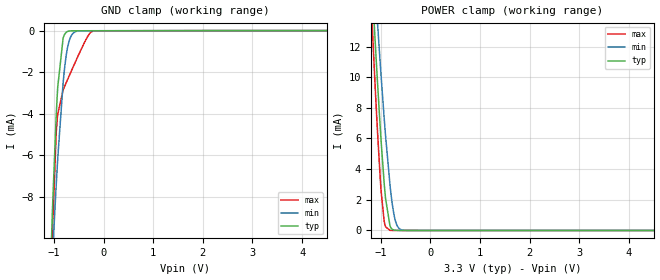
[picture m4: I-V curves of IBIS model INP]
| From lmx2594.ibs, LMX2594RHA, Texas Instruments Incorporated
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|   Model INP
[Model]   INP
Model_type   Input
Vinl = .4
Vinh = 1.4
|   typ   min   max
|   (nom PVT)   (slow PVT)   (fast PVT)
C_comp   0.097p   0.055p   0.172p
[Voltage Range]   3.3   3   3.6
[Temperature Range]   27   125   -40
[Power Clamp Reference]   3.3   3   3.6
[GND Clamp Reference]   0   0   0
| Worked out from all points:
|   GND clamp passes 1 mA (typ) near -0.84 V on its own axis
|   POWER clamp passes 1 mA (typ) near -0.85 V on its own axis
[GND Clamp]
|   Voltage   I(typ)   I(min)   I(max)
-3.3V     -246.7mA   -151.3mA   -472.5mA
-1.063V   -10.99mA   -12.47mA   -13.38mA
-1.043V   -9.526mA   -11.49mA   -11.15mA
-1.033V   -8.823mA   -11.01mA   -10.14mA
-1.023V   -8.14mA    -10.54mA   -9.21mA
-953.7mV  -4.036mA   -7.394mA   -4.875mA
-924mV    -2.719mA   -6.164mA   -4.026mA
-815.1mV  -359.4uA   -2.508mA   -2.855mA
-726mV    -41.2uA    -819.4uA   -2.358mA
-597.3mV  -10.68uA   -94.98uA   -1.663mA
-211.2mV  -9.103uA   -7.806uA   -22.77uA
6.6V      0A         0A         0A
[POWER Clamp]
|   Voltage   I(typ)   I(min)   I(max)
-3.3V     164.1mA    142.7mA    184.6mA
-1.27V    21.95mA    24.01mA    20.35mA
-1.162V   15.17mA    18.29mA    12.57mA
-1.112V   12.23mA    15.77mA    9.255mA
-1.073V   9.96mA     13.8mA     6.765mA
-993.3mV  5.782mA    10.03mA    2.547mA
-924mV    2.765mA    6.978mA    472uA
-815.1mV  299.5uA    2.966mA    9.519uA
-755.7mV  53.96uA    1.431mA    2.479uA
-696.3mV  9.978uA    523.6uA    1.72uA
-537.9mV  1.219uA    16.89uA    1.015uA
6.6V      0A         0A         0A
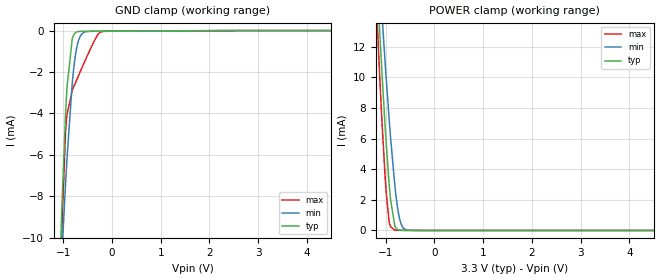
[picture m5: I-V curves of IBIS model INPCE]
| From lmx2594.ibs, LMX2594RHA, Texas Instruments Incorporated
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|   Model INPCE
[Model]   INPCE
Model_type   Input
Vinl = .4
Vinh = 1.4
|   typ   min   max
|   (nom PVT)   (slow PVT)   (fast PVT)
C_comp   0.097p   0.055p   0.172p
[Voltage Range]   3.3   3   3.6
[Temperature Range]   27   125   -40
[Power Clamp Reference]   3.3   3   3.6
[GND Clamp Reference]   0   0   0
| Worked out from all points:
|   GND clamp passes 1 mA (typ) near -0.84 V on its own axis
|   POWER clamp passes 1 mA (typ) near -0.85 V on its own axis
[GND Clamp]
|   Voltage   I(typ)   I(min)   I(max)
-3.3V     -246.7mA   -151.3mA   -472.6mA
-1.063V   -11.02mA   -12.49mA   -13.41mA
-1.043V   -9.555mA   -11.52mA   -11.18mA
-1.033V   -8.852mA   -11.04mA   -10.17mA
-1.023V   -8.169mA   -10.56mA   -9.241mA
-953.7mV  -4.065mA   -7.42mA    -4.906mA
-924mV    -2.747mA   -6.19mA    -4.056mA
-815.1mV  -386.5uA   -2.533mA   -2.884mA
-726mV    -67.58uA   -843.8uA   -2.387mA
-597.3mV  -35.97uA   -118.2uA   -1.691mA
-201.3mV  -31.01uA   -27.72uA   -42.5uA
6.6V      0A         0A         0A
[POWER Clamp]
|   Voltage   I(typ)   I(min)   I(max)
-3.3V     164.1mA    142.7mA    184.6mA
-1.27V    21.97mA    24.03mA    20.37mA
-1.162V   15.19mA    18.31mA    12.59mA
-1.112V   12.24mA    15.79mA    9.272mA
-1.073V   9.975mA    13.82mA    6.781mA
-993.3mV  5.796mA    10.04mA    2.561mA
-924mV    2.777mA    6.991mA    484.6uA
-815.1mV  309.7uA    2.977mA    19.73uA
-755.7mV  63.05uA    1.441mA    11.38uA
-696.3mV  17.92uA    532.6uA    9.321uA
-537.9mV  6.163uA    23.15uA    5.233uA
6.6V      0A         0A         0A
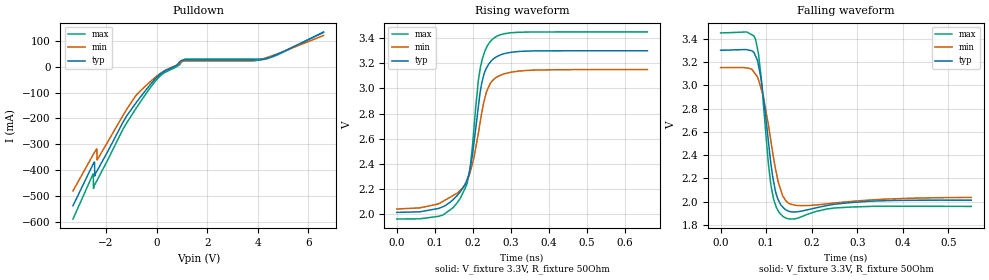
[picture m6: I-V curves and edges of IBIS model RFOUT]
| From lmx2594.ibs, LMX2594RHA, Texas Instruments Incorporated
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|   Model RFOUT
[Model]   RFOUT
Model_type   Open_drain
Polarity   Non-Inverting
Vmeas = 2.5
Vref = 3.3
Cref = 15pF
Rref = 50
|   typ   min   max
|   (nom PVT)   (slow PVT)   (fast PVT)
C_comp   0.263p   0.255p   0.278p
[Voltage Range]   3.3   3.15   3.45
[Temperature Range]   27   125   -40
[Pullup Reference]   3.3   3.15   3.45
[Pulldown Reference]   0   0   0
[Power Clamp Reference]   3.3   3.15   3.45
[GND Clamp Reference]   0   0   0
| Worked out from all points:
|   slope of the pulldown table from 0 to 0.495 V, typ, clamps not added: 14.7 ohm
|   falling waveform, V_fixture 3.3V, R_fixture 50Ohm: 20-80 % time 23ps typ, 29.5ps min, 20.5ps max; typ from 3.3 V to 2.01 V
|   rising waveform, V_fixture 3.3V, R_fixture 50Ohm: 20-80 % time 39ps typ, 48.7ps min, 32.8ps max; typ from 2.01 V to 3.3 V
[Pulldown]
|   Voltage   I(typ)   I(min)   I(max)
-3.3V     -538.2mA   -480.8mA   -589.5mA
-2.508V   -377.7mA   -341.3mA   -416mA
-2.488V   -374.3mA   -338mA     -471.4mA
-2.449V   -368.8mA   -331.5mA   -457.5mA
-2.439V   -423.1mA   -329.9mA   -455.8mA
-2.36V    -404.9mA   -318.3mA   -441.9mA
-2.34V    -401.6mA   -359.9mA   -438.3mA
-1.181V   -191.1mA   -165.1mA   -218.1mA
293.7mV   -18.37mA   -17.23mA   -24.65mA
1.125V    25.61mA    21.92mA    28.98mA
4.155V    26.22mA    28.77mA    29.73mA
6.6V      132.7mA    120.7mA    134.3mA
[Ramp]
R_load = 50
|   typ   min   max
dV/dt_r   0.772733/3.89944e-11   0.666569/4.86919e-11   0.894467/3.28412e-11
dV/dt_f   0.772293/2.30105e-11   0.668022/2.93836e-11   0.894195/2.04418e-11
[Falling Waveform]
V_fixture = 3.3V
V_fixture_min = 3.15V
V_fixture_max = 3.45V
R_fixture = 50Ohm
C_fixture = 0F
|   Time   V(typ)   V(min)   V(max)
0s        3.302V     3.153V     3.452V
76.49ps   3.253V     3.097V     3.399V
88.8ps    3.059V     2.973V     3.072V
104.6ps   2.528V     2.667V     2.335V
110.4ps   2.328V     2.522V     2.143V
121.7ps   2.069V     2.258V     1.957V
137.3ps   1.951V     2.044V     1.872V
176.1ps   1.918V     1.966V     1.869V
248.9ps   1.978V     1.989V     1.946V
550ps     2.013V     2.037V     1.96V
[Rising Waveform]
V_fixture = 3.3V
V_fixture_min = 3.15V
V_fixture_max = 3.45V
R_fixture = 50Ohm
C_fixture = 0F
|   Time   V(typ)   V(min)   V(max)
0s        2.012V     2.039V     1.959V
110ps     2.044V     2.08V      1.981V
167.3ps   2.177V     2.189V     2.125V
193ps     2.363V     2.33V      2.366V
214.6ps   2.85V      2.639V     3.06V
220.4ps   2.985V     2.746V     3.172V
236.5ps   3.164V     2.975V     3.327V
255.9ps   3.239V     3.074V     3.402V
340.9ps   3.297V     3.143V     3.449V
660ps     3.3V       3.15V      3.45V
